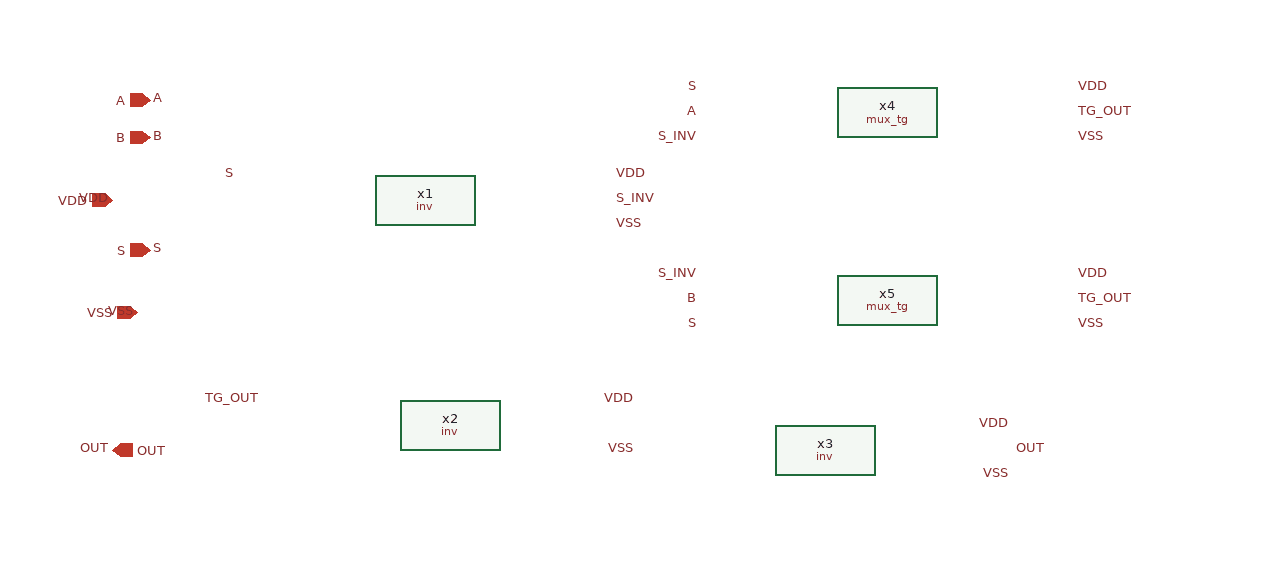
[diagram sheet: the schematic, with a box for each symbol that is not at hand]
v {xschem version=3.4.7 file_version=1.2}
G {}
K {}
V {}
S {}
E {}
P 4 1 350 -250 {}
C {iopin.sym} -610 -170 0 0 {name=p1 lab=VDD}
C {opin.sym} -610 30 0 0 {name=p5 lab=OUT}
C {ipin.sym} -580 -250 0 0 {name=p6 lab=A}
C {ipin.sym} -580 -220 0 0 {name=p7 lab=B}
C {ipin.sym} -580 -130 0 0 {name=p8 lab=S}
C {iopin.sym} -590 -80 0 0 {name=p4 lab=VSS}
C {lab_wire.sym} -210 -190 0 1 {name=p2 sig_type=std_logic lab=VDD}
C {lab_wire.sym} -210 -150 0 1 {name=p3 sig_type=std_logic lab=VSS}
C {lab_wire.sym} 160 -70 0 1 {name=p9 sig_type=std_logic lab=VSS}
C {lab_wire.sym} 160 -260 0 1 {name=p10 sig_type=std_logic lab=VDD}
C {lab_wire.sym} 160 -110 0 1 {name=p11 sig_type=std_logic lab=VDD}
C {lab_wire.sym} 160 -220 0 1 {name=p12 sig_type=std_logic lab=VSS}
C {lab_wire.sym} -610 -170 0 0 {name=p13 sig_type=std_logic lab=VDD}
C {lab_wire.sym} -590 -80 0 0 {name=p14 sig_type=std_logic lab=VSS}
C {lab_wire.sym} -190 -10 1 0 {name=p15 sig_type=std_logic lab=VDD}
C {lab_wire.sym} 110 10 1 0 {name=p16 sig_type=std_logic lab=VDD}
C {lab_wire.sym} -190 30 1 1 {name=p17 sig_type=std_logic lab=VSS}
C {lab_wire.sym} 110 50 1 1 {name=p18 sig_type=std_logic lab=VSS}
C {lab_wire.sym} -140 -260 0 0 {name=p19 sig_type=std_logic lab=S}
C {lab_wire.sym} -140 -70 0 0 {name=p20 sig_type=std_logic lab=S}
C {lab_wire.sym} -210 -170 0 1 {name=p21 sig_type=std_logic lab=S_INV}
C {lab_wire.sym} -140 -110 0 0 {name=p22 sig_type=std_logic lab=S_INV}
C {lab_wire.sym} -140 -220 0 0 {name=p23 sig_type=std_logic lab=S_INV}
C {lab_wire.sym} -580 -130 0 1 {name=p24 sig_type=std_logic lab=S}
C {lab_wire.sym} -510 -190 0 0 {name=p25 sig_type=std_logic lab=S}
C {lab_wire.sym} -140 -240 0 0 {name=p26 sig_type=std_logic lab=A}
C {lab_wire.sym} -140 -90 0 0 {name=p27 sig_type=std_logic lab=B}
C {lab_wire.sym} -580 -250 0 1 {name=p28 sig_type=std_logic lab=A}
C {lab_wire.sym} -580 -220 0 1 {name=p29 sig_type=std_logic lab=B}
C {lab_wire.sym} 160 -240 0 1 {name=p30 sig_type=std_logic lab=TG_OUT}
C {lab_wire.sym} 160 -90 0 1 {name=p31 sig_type=std_logic lab=TG_OUT}
C {lab_wire.sym} -490 -10 0 0 {name=p32 sig_type=std_logic lab=TG_OUT}
C {lab_wire.sym} -610 30 0 0 {name=p33 sig_type=std_logic lab=OUT}
C {lab_wire.sym} 110 30 0 1 {name=p34 sig_type=std_logic lab=OUT}
C {cells/sdffrq/sch/inv.sym} -360 -170 0 0 {name=x1}
C {cells/sdffrq/sch/inv.sym} -340 10 0 0 {name=x2}
C {cells/sdffrq/sch/inv.sym} -40 30 0 0 {name=x3}
C {cells/sdffrq/sch/mux_tg.sym} 10 -240 0 0 {name=x4}
C {cells/sdffrq/sch/mux_tg.sym} 10 -90 0 0 {name=x5}
